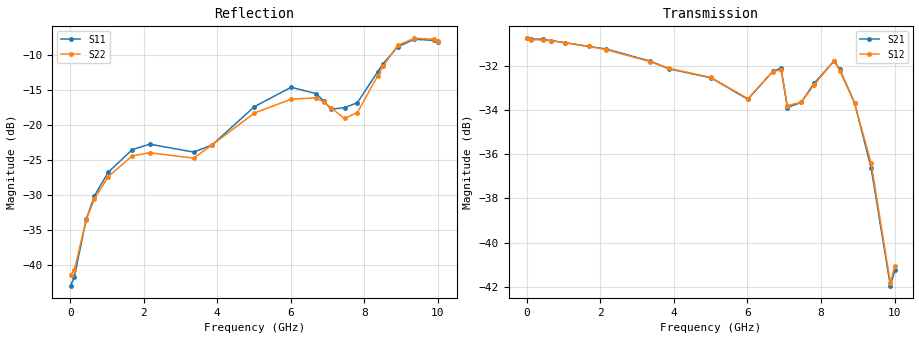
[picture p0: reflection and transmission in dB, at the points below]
! Device ID: PE43705
! Serial: 1
! Insertion: A
! Impedance: 50 ohm
! Temp: 25C
! VDD: 3.400V
! Attenuation Step: 29.75dB
#  Hz  S  RI  R  50
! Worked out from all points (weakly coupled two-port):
!   401 points, 10 MHz to 10.01 GHz, reference 50 ohm
!   highest |S21| = -30.76 dB at 10 MHz (marker M1); lowest = -42.0 dB at 9.885 GHz (marker M2)
!   lowest |S11| = -43.0 dB at 10 MHz (marker M3), VSWR 1.01, Z = 49.3 + j0.0442 ohm
!   |S11| at or under -10 dB: start of sweep to 8.692 GHz
!   |S22| runs from -41.5 to -7.5 dB; largest |S21 - S12| = 0.00066
!   S11 on the Smith chart (normalised r, x): 10 MHz: 0.99, +0.00; 7.46 GHz: 0.82, +0.16; 8.51 GHz: 0.82, +0.48; 9.36 GHz: 0.55, +0.48; 10.01 GHz: 0.48, +0.26
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1e7  -0.00704 0.000448  0.029 -9.65e-05  0.029 -0.000111  -0.00838 0.000506
1.1e8  -0.00665 0.00461  0.0289 -0.000788  0.0288 -0.000828  -0.00781 0.00462
4.35e8  -0.0118 0.0174  0.0287 -0.00308  0.0286 -0.00296  -0.0122 0.0169
6.6e8  -0.02 0.0237  0.0283 -0.00451  0.0283 -0.00446  -0.0191 0.0226
1.035e9  -0.0372 0.0266  0.0275 -0.0069  0.0275 -0.00686  -0.0339 0.0256
1.685e9  -0.0642 0.0165  0.0257 -0.0106  0.0257 -0.0106  -0.0571 0.0179
2.16e9  -0.0725 0.00294  0.0241 -0.0131  0.024 -0.0131  -0.0625 0.00777
3.36e9  -0.0636 0.00322  0.0186 -0.0178  0.0185 -0.0178  -0.0563 0.0123
3.86e9  -0.0668 0.026  0.0162 -0.0187  0.0163 -0.0187  -0.0666 0.0269
5.01e9  -0.1034 0.0862  0.0122 -0.0202  0.0123 -0.0202  -0.1026 0.0643
6.01e9  -0.1559 0.1001  0.00757 -0.0197  0.00777 -0.0197  -0.1303 0.0792
6.685e9  -0.1465 0.0795  0.0062 -0.0236  0.00638 -0.0235  -0.137 0.0729
6.91e9  -0.1285 0.0707  0.00266 -0.0247  0.00274 -0.0245  -0.1255 0.0724
7.085e9  -0.1134 0.0614  0.000766 -0.0202  0.000824 -0.0204  -0.1079 0.0768
7.46e9  -0.0929 0.0943  0.00262 -0.0206  0.00276 -0.0206  -0.0723 0.084
7.81e9  -0.0487 0.1352  0.00248 -0.0228  0.00266 -0.0226  -0.0478 0.1125
8.36e9  -0.0161 0.238  -0.00561 -0.0252  -0.00556 -0.0252  -0.0364 0.2196
8.51e9  -0.0253 0.2722  -0.00838 -0.0232  -0.00809 -0.0231  -0.0455 0.2587
8.91e9  -0.0801 0.3516  -0.0117 -0.0171  -0.0117 -0.0171  -0.107 0.3539
9.36e9  -0.1809 0.3661  -0.0101 -0.0108  -0.0103 -0.0111  -0.1994 0.3633
9.885e9  -0.2967 0.2697  -0.00271 -0.00751  -0.00276 -0.00763  -0.3254 0.2474
1.001e10  -0.3142 0.2276  -0.000724 -0.00863  -0.000734 -0.00883  -0.3468 0.198
